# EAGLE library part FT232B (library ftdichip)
USB to serial UART interface Source: DS_FT232BL_BQ.pdf

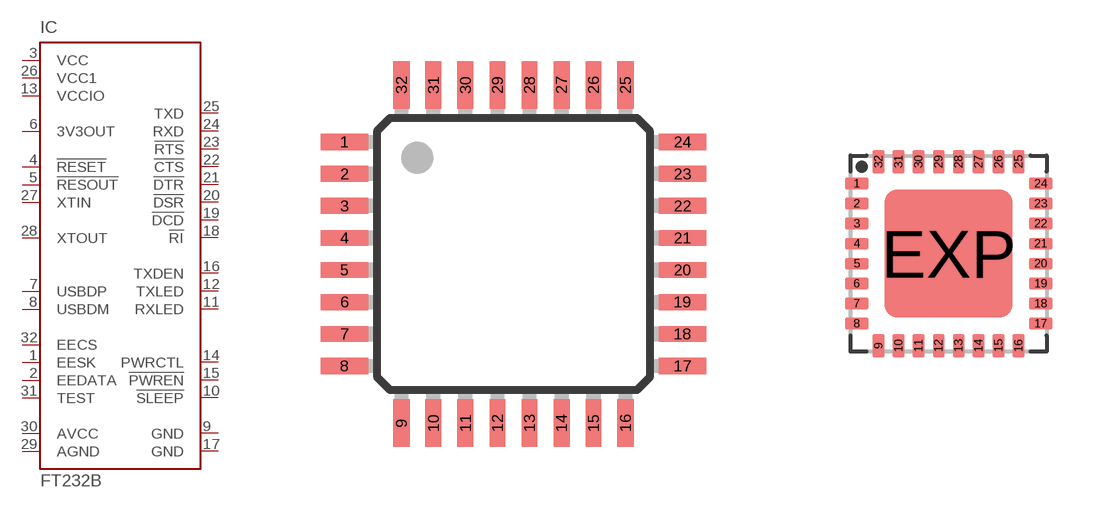
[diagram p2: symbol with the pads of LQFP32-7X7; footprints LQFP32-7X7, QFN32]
Designator prefix IC

## FT232BL (MF: FARNELL; MPN: FT232BL/TR; OC_FARNELL: unknown; OC_NEWARK: 38K1551)  [LQFP32-7X7]
1  EESK  in
2  EEDATA  in
3  VCC  pwr
4  !RESET  in
5  !RESOUT  in
6  3V3OUT  out
7  USBDP
8  USBDM
9  GND  pwr
10  !SLEEP  in
11  RXLED
12  TXLED
13  VCCIO  pwr
14  PWRCTL
15  !PWREN
16  TXDEN
17  GND  pwr
18  !RI  in
19  !DCD  in
20  !DSR  in
21  !DTR  out
22  !CTS  in
23  !RTS  out
24  RXD  in
25  TXD  out
26  VCC1  pwr
27  XTIN  in
28  XTOUT  out
29  AGND  pwr
30  AVCC  pwr
31  TEST  in
32  EECS  in

## FT232BQ (OC_FARNELL: unknown; OC_NEWARK: unknown)  [QFN32]
Pads as for LQFP32-7X7

## Footprint LQFP32-7X7 (pad centres in mm)
32-LD LQFP 7 x 7 mm Source: DS_FT232BL_BQ.pdf
smd 1.2 x 0.4: 1 -4.225,2.8; 2 -4.225,2; 3 -4.225,1.2; 4 -4.225,0.4; 5 -4.225,-0.4; 6 -4.225,-1.2; 7 -4.225,-2; 8 -4.225,-2.8; 17 4.225,-2.8; 18 4.225,-2; 19 4.225,-1.2; 20 4.225,-0.4; 21 4.225,0.4; 22 4.225,1.2; 23 4.225,2; 24 4.225,2.8
smd 0.4 x 1.2: 9 -2.8,-4.225; 10 -2,-4.225; 11 -1.2,-4.225; 12 -0.4,-4.225; 13 0.4,-4.225; 14 1.2,-4.225; 15 2,-4.225; 16 2.8,-4.225; 25 2.8,4.225; 26 2,4.225; 27 1.2,4.225; 28 0.4,4.225; 29 -0.4,4.225; 30 -1.2,4.225; 31 -2,4.225; 32 -2.8,4.225

## Footprint QFN32 (pad centres in mm)
QFN 32 Source: http://www.ftdichip.com/Documents/DataSheets/DS_FT232R_v104.pdf
smd 0.6 x 0.3: 1 -2.3,1.75; 2 -2.3,1.25; 3 -2.3,0.75; 4 -2.3,0.25; 5 -2.3,-0.25; 6 -2.3,-0.75; 7 -2.3,-1.25; 8 -2.3,-1.75; 17 2.3,-1.75; 18 2.3,-1.25; 19 2.3,-0.75; 20 2.3,-0.25; 21 2.3,0.25; 22 2.3,0.75; 23 2.3,1.25; 24 2.3,1.75
smd 0.3 x 0.6: 9 -1.75,-2.3; 10 -1.25,-2.3; 11 -0.75,-2.3; 12 -0.25,-2.3; 13 0.25,-2.3; 14 0.75,-2.3; 15 1.25,-2.3; 16 1.75,-2.3; 25 1.75,2.3; 26 1.25,2.3; 27 0.75,2.3; 28 0.25,2.3; 29 -0.25,2.3; 30 -0.75,2.3; 31 -1.25,2.3; 32 -1.75,2.3
smd 3.2 x 3.2: EXP 0,0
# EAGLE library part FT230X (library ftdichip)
USB to BASIC UART IC Auto generated by make-symbol-device-package-bsdl.ulp Rev. 43 Source: Data sheet

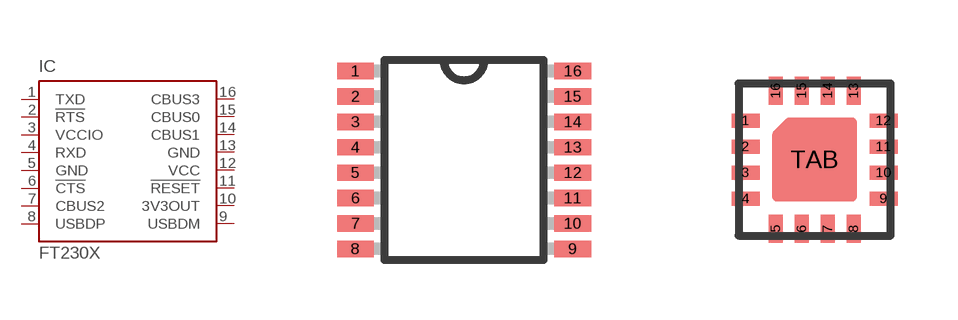
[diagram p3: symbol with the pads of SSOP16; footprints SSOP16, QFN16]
Designator prefix IC

## FT230XS  [SSOP16]
1  TXD  out
2  !RTS  out
3  VCCIO  pwr
4  RXD  in
5  GND  pwr
6  !CTS  in
7  CBUS2
8  USBDP  in
9  USBDM  in
10  3V3OUT  out
11  !RESET  in
12  VCC  pwr
13  GND  pwr
14  CBUS1
15  CBUS0
16  CBUS3

## FT230XQ  [QFN16]
1  VCCIO  pwr
2  RXD  in
3  GND  pwr
4  !CTS  in
5  CBUS2
6  USBDP  in
7  USBDM  in
8  3V3OUT  out
9  !RESET  in
10  VCC  pwr
11  CBUS1
12  CBUS0
13  GND  pwr
14  CBUS3
15  TXD  out
16  !RTS  out

## Footprint SSOP16 (pad centres in mm)
SSOP-16 Auto generated by make-symbol-device-package-bsdl.ulp Rev. 43 Source: Data sheet
smd 0.914 x 0.406: 1 -2.718,2.223; 2 -2.718,1.587; 3 -2.718,0.953; 4 -2.718,0.318; 5 -2.718,-0.318; 6 -2.718,-0.953; 7 -2.718,-1.587; 8 -2.718,-2.223; 9 2.718,-2.223; 10 2.718,-1.587; 11 2.718,-0.953; 12 2.718,-0.318; 13 2.718,0.318; 14 2.718,0.953; 15 2.718,1.587; 16 2.718,2.223

## Footprint QFN16 (pad centres in mm)
QFN-16 4 x 4 mm Source: Data sheet
smd 0.7 x 0.35: 1 -1.725,0.975; 2 -1.725,0.325; 3 -1.725,-0.325; 4 -1.725,-0.975; 9 1.725,-0.975; 10 1.725,-0.325; 11 1.725,0.325; 12 1.725,0.975
smd 0.35 x 0.7: 5 -0.975,-1.725; 6 -0.325,-1.725; 7 0.325,-1.725; 8 0.975,-1.725; 13 0.975,1.725; 14 0.325,1.725; 15 -0.325,1.725; 16 -0.975,1.725
smd 1 x 1: TAB 0,0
